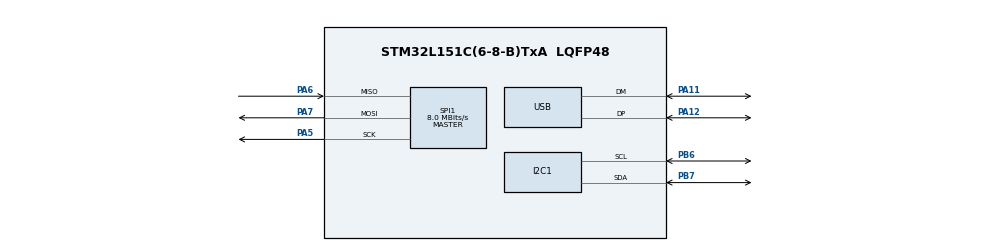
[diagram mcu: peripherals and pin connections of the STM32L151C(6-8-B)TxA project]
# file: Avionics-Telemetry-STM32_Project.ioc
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Mcu.Family=STM32L1
Mcu.Name=STM32L151C(6-8-B)TxA
Mcu.Package=LQFP48
NVIC.PriorityGroup=NVIC_PRIORITYGROUP_4
NVIC.USB_LP_IRQn=true\:0\:0\:false\:false\:true\:false\:true
PA11.Mode=Device
PA11.Signal=USB_DM
PA12.Mode=Device
PA12.Signal=USB_DP
PA5.Mode=Full_Duplex_Master
PA5.Signal=SPI1_SCK
PA6.Mode=Full_Duplex_Master
PA6.Signal=SPI1_MISO
PA7.Mode=Full_Duplex_Master
PA7.Signal=SPI1_MOSI
PB6.Mode=I2C
PB6.Signal=I2C1_SCL
PB7.Mode=I2C
PB7.Signal=I2C1_SDA
PH0-OSC_IN.Mode=HSE-External-Oscillator
PH0-OSC_IN.Signal=RCC_OSC_IN
PH1-OSC_OUT.Mode=HSE-External-Oscillator
PH1-OSC_OUT.Signal=RCC_OSC_OUT
ProjectManager.HeapSize=0x200
ProjectManager.StackSize=0x400
ProjectManager.TargetToolchain=STM32CubeIDE
RCC.48MHZClocksFreq_Value=48000000
RCC.AHBFreq_Value=16000000
RCC.APB1Freq_Value=16000000
RCC.APB1TimFreq_Value=16000000
RCC.APB2Freq_Value=16000000
RCC.APB2TimFreq_Value=16000000
RCC.HCLKFreq_Value=16000000
RCC.HSE_VALUE=24000000
RCC.HSI_VALUE=16000000
RCC.LSE_VALUE=32768
RCC.MSI_VALUE=2097000
RCC.PLLMUL=RCC_PLL_MUL4
RCC.SYSCLKFreq_VALUE=16000000
RCC.SYSCLKSource=RCC_SYSCLKSOURCE_HSI
RCC.VCOOutputFreq_Value=96000000
SPI1.CalculateBaudRate=8.0 MBits/s
SPI1.Direction=SPI_DIRECTION_2LINES
SPI1.Mode=SPI_MODE_MASTER
SPI1.VirtualType=VM_MASTER
USB_DEVICE.CLASS_NAME_FS=MSC
USB_DEVICE.VirtualMode=Msc
USB_DEVICE.VirtualModeFS=Msc_FS
VP_USB_DEVICE_VS_USB_DEVICE_MSC_FS.Mode=MSC_FS
board=custom

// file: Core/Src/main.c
/* USER CODE BEGIN Header */
/**
  ******************************************************************************
  * @file           : main.c
  * @brief          : Main program body
  ******************************************************************************
  * @attention
  *
  * <h2><center>&copy; Copyright (c) 2021 STMicroelectronics.
  * All rights reserved.</center></h2>
  *
  * This software component is licensed by ST under BSD 3-Clause license,
  * the "License"; You may not use this file except in compliance with the
  * License. You may obtain a copy of the License at:
  *                        opensource.org/licenses/BSD-3-Clause
  *
  ******************************************************************************
  */
/* USER CODE END Header */
#include "main.h"
#include "usb_device.h"

I2C_HandleTypeDef hi2c1;

SPI_HandleTypeDef hspi1;

void SystemClock_Config(void);
static void MX_GPIO_Init(void);
static void MX_I2C1_Init(void);
static void MX_SPI1_Init(void);

int main(void)
{

  /* MCU Configuration--------------------------------------------------------*/

  /* Reset of all peripherals, Initializes the Flash interface and the Systick. */
  HAL_Init();

  /* Configure the system clock */
  SystemClock_Config();

  /* Initialize all configured peripherals */
  MX_GPIO_Init();
  MX_I2C1_Init();
  MX_SPI1_Init();
  MX_USB_DEVICE_Init();

  /* Infinite loop */
  while (1)
  {

  }
}

void SystemClock_Config(void)
{
  RCC_OscInitTypeDef RCC_OscInitStruct = {0};
  RCC_ClkInitTypeDef RCC_ClkInitStruct = {0};

  /** Configure the main internal regulator output voltage
  */
  __HAL_PWR_VOLTAGESCALING_CONFIG(PWR_REGULATOR_VOLTAGE_SCALE1);
  /** Initializes the RCC Oscillators according to the specified parameters
  * in the RCC_OscInitTypeDef structure.
  */
  RCC_OscInitStruct.OscillatorType = RCC_OSCILLATORTYPE_HSI|RCC_OSCILLATORTYPE_MSI;
  RCC_OscInitStruct.HSIState = RCC_HSI_ON;
  RCC_OscInitStruct.HSICalibrationValue = RCC_HSICALIBRATION_DEFAULT;
  RCC_OscInitStruct.MSIState = RCC_MSI_ON;
  RCC_OscInitStruct.MSICalibrationValue = 0;
  RCC_OscInitStruct.MSIClockRange = RCC_MSIRANGE_5;
  RCC_OscInitStruct.PLL.PLLState = RCC_PLL_ON;
  RCC_OscInitStruct.PLL.PLLSource = RCC_PLLSOURCE_HSI;
  RCC_OscInitStruct.PLL.PLLMUL = RCC_PLL_MUL3;
  RCC_OscInitStruct.PLL.PLLDIV = RCC_PLL_DIV2;
  if (HAL_RCC_OscConfig(&RCC_OscInitStruct) != HAL_OK)
  {
    Error_Handler();
  }
  /** Initializes the CPU, AHB and APB buses clocks
  */
  RCC_ClkInitStruct.ClockType = RCC_CLOCKTYPE_HCLK|RCC_CLOCKTYPE_SYSCLK
                              |RCC_CLOCKTYPE_PCLK1|RCC_CLOCKTYPE_PCLK2;
  RCC_ClkInitStruct.SYSCLKSource = RCC_SYSCLKSOURCE_MSI;
  RCC_ClkInitStruct.AHBCLKDivider = RCC_SYSCLK_DIV1;
  RCC_ClkInitStruct.APB1CLKDivider = RCC_HCLK_DIV1;
  RCC_ClkInitStruct.APB2CLKDivider = RCC_HCLK_DIV1;

  if (HAL_RCC_ClockConfig(&RCC_ClkInitStruct, FLASH_LATENCY_0) != HAL_OK)
  {
    Error_Handler();
  }
}

static void MX_I2C1_Init(void)
{

  hi2c1.Instance = I2C1;
  hi2c1.Init.ClockSpeed = 100000;
  hi2c1.Init.DutyCycle = I2C_DUTYCYCLE_2;
  hi2c1.Init.OwnAddress1 = 0;
  hi2c1.Init.AddressingMode = I2C_ADDRESSINGMODE_7BIT;
  hi2c1.Init.DualAddressMode = I2C_DUALADDRESS_DISABLE;
  hi2c1.Init.OwnAddress2 = 0;
  hi2c1.Init.GeneralCallMode = I2C_GENERALCALL_DISABLE;
  hi2c1.Init.NoStretchMode = I2C_NOSTRETCH_DISABLE;
  if (HAL_I2C_Init(&hi2c1) != HAL_OK)
  {
    Error_Handler();
  }

}

static void MX_SPI1_Init(void)
{

  /* SPI1 parameter configuration*/
  hspi1.Instance = SPI1;
  hspi1.Init.Mode = SPI_MODE_MASTER;
  hspi1.Init.Direction = SPI_DIRECTION_2LINES;
  hspi1.Init.DataSize = SPI_DATASIZE_8BIT;
  hspi1.Init.CLKPolarity = SPI_POLARITY_LOW;
  hspi1.Init.CLKPhase = SPI_PHASE_1EDGE;
  hspi1.Init.NSS = SPI_NSS_SOFT;
  hspi1.Init.BaudRatePrescaler = SPI_BAUDRATEPRESCALER_2;
  hspi1.Init.FirstBit = SPI_FIRSTBIT_MSB;
  hspi1.Init.TIMode = SPI_TIMODE_DISABLE;
  hspi1.Init.CRCCalculation = SPI_CRCCALCULATION_DISABLE;
  hspi1.Init.CRCPolynomial = 10;
  if (HAL_SPI_Init(&hspi1) != HAL_OK)
  {
    Error_Handler();
  }

}

static void MX_GPIO_Init(void)
{

  /* GPIO Ports Clock Enable */
  __HAL_RCC_GPIOH_CLK_ENABLE();
  __HAL_RCC_GPIOA_CLK_ENABLE();
  __HAL_RCC_GPIOB_CLK_ENABLE();

}

void Error_Handler(void)
{
  __disable_irq();
  while (1)
  {
  }
}

/************************ (C) COPYRIGHT STMicroelectronics *****END OF FILE****/
